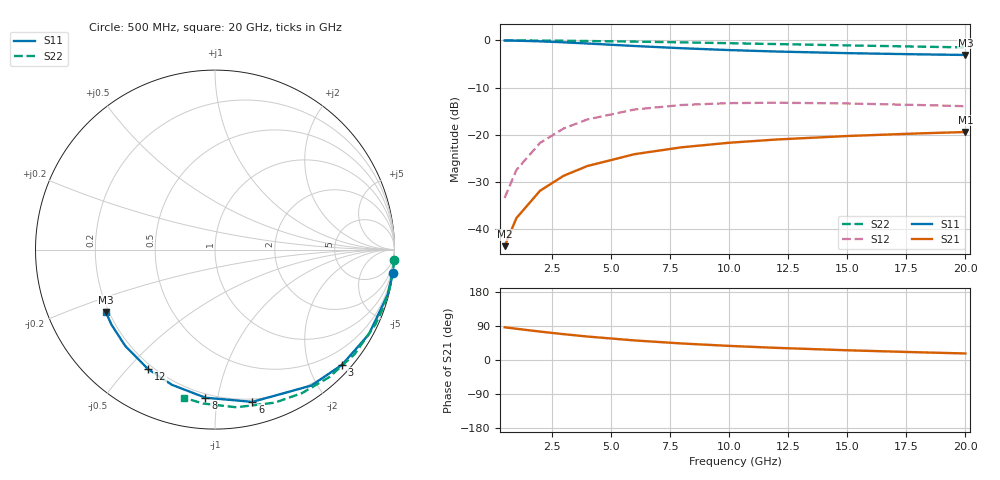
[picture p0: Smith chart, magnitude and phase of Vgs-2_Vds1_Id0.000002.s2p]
# Hz S RI R 50
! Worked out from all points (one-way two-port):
!   12 points, 500 MHz to 20 GHz, reference 50 ohm
!   highest |S21| = -19.42 dB at 20 GHz (marker M1); lowest = -43.6 dB at 500 MHz (marker M2)
!   lowest |S11| = -3.1 dB at 20 GHz (marker M3), VSWR 5.70, Z = 9.37 - j12.9 ohm
!   |S11| at or under -10 dB: nowhere
!   |S22| runs from -1.5 to 0.0 dB; largest |S21 - S12| = 0.15
!   S11 on the Smith chart (normalised r, x): 500 MHz: 0, -16; 3 GHz: 0.18, -2.58; 6 GHz: 0.18, -1.26; 8 GHz: 0.18, -0.92; 12 GHz: 0.18, -0.57; 20 GHz: 0.19, -0.26
5e8  0.9904 -0.1277  0.000423 0.00658  0.00206 0.0213  0.9982 -0.0552
1e9  0.9621 -0.2513  0.00173 0.013  0.00809 0.0416  0.993 -0.1101
2e9  0.8571 -0.472  0.00661 0.0246  0.0302 0.0762  0.9723 -0.2177
3e9  0.7071 -0.6424  0.0137 0.0341  0.0612 0.0993  0.9389 -0.3203
4e9  0.5367 -0.7575  0.0219 0.0411  0.0951 0.1099  0.8941 -0.4164
6e9  0.2081 -0.8484  0.0387 0.0488  0.1552 0.1015  0.7777 -0.5827
8e9  -0.053 -0.8251  0.0534 0.0508  0.1942 0.0718  0.6364 -0.7109
1e10  -0.2412 -0.7529  0.0655 0.0498  0.2133 0.0373  0.4847 -0.7996
1.2e10  -0.3731 -0.6656  0.0755 0.0473  0.2187 0.00554  0.3326 -0.8528
1.5e10  -0.5007 -0.5359  0.0875 0.042  0.2123 -0.032  0.1191 -0.8786
1.8e10  -0.576 -0.4195  0.0969 0.036  0.1986 -0.0579  -0.0658 -0.8575
2e10  -0.6081 -0.3501  0.1021 0.0317  0.1882 -0.0701  -0.1716 -0.8261
